VERSION 5.7 ;
  NOWIREEXTENSIONATPIN ON ;
  DIVIDERCHAR "/" ;
  BUSBITCHARS "[]" ;
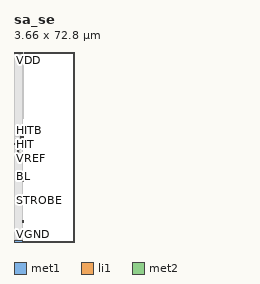
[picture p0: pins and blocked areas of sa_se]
MACRO sa_se
  CLASS BLOCK ;
  FOREIGN sa_se ;
  ORIGIN 0.300 -0.200 ;
  SIZE 3.660 BY 72.800 ;
  PIN VGND
    USE GROUND ;
    PORT
      LAYER met1 ;
        RECT -0.300 0.200 2.900 0.700 ;
    END
    PORT
      LAYER li1 ;
        RECT 2.900 7.550 3.320 8.450 ;
    END
    PORT
      LAYER li1 ;
        RECT 2.900 23.550 3.320 24.450 ;
    END
    PORT
      LAYER li1 ;
        RECT 2.900 39.550 3.320 40.450 ;
    END
  END VGND
  PIN VDD
      USE POWER ;
    ANTENNADIFFAREA 5.527200 ;
    PORT
      LAYER met2 ;
        RECT -0.300 72.300 2.900 72.800 ;
    END
  END VDD
  PIN BL
    ANTENNAGATEAREA 16.000000 ;
    PORT
      LAYER met2 ;
        RECT 1.150 25.100 1.430 25.700 ;
    END
  END BL
  PIN VREF
    ANTENNAGATEAREA 16.000000 ;
    PORT
      LAYER met2 ;
        RECT 1.150 34.600 1.430 35.200 ;
    END
  END VREF
  PIN HIT
    ANTENNAGATEAREA 12.000000 ;
    ANTENNADIFFAREA 3.723600 ;
    PORT
      LAYER met2 ;
        RECT 0.060 37.400 0.340 37.900 ;
    END
  END HIT
  PIN HITB
    ANTENNAGATEAREA 12.000000 ;
    ANTENNADIFFAREA 3.723600 ;
    PORT
      LAYER met2 ;
        RECT 2.260 40.000 2.540 40.500 ;
    END
  END HITB
  PIN STROBE
    ANTENNAGATEAREA 15.679999 ;
    PORT
      LAYER met2 ;
        RECT 2.800 16.000 3.080 16.500 ;
    END
  END STROBE
  OBS
      LAYER nwell ;
        RECT -0.300 47.500 3.150 73.000 ;
      LAYER li1 ;
        RECT 0.060 40.620 2.920 72.055 ;
        RECT 0.060 39.380 2.730 40.620 ;
        RECT 0.060 24.620 2.920 39.380 ;
        RECT 0.060 23.380 2.730 24.620 ;
        RECT 0.060 8.620 2.920 23.380 ;
        RECT 0.060 7.380 2.730 8.620 ;
        RECT 0.060 5.080 2.920 7.380 ;
      LAYER met1 ;
        RECT 0.010 0.980 3.130 72.160 ;
      LAYER met2 ;
        RECT 0.010 40.780 3.130 72.020 ;
        RECT 0.010 39.720 1.980 40.780 ;
        RECT 2.820 39.720 3.130 40.780 ;
        RECT 0.010 38.180 3.130 39.720 ;
        RECT 0.620 37.120 3.130 38.180 ;
        RECT 0.010 35.480 3.130 37.120 ;
        RECT 0.010 34.320 0.870 35.480 ;
        RECT 1.710 34.320 3.130 35.480 ;
        RECT 0.010 25.980 3.130 34.320 ;
        RECT 0.010 24.820 0.870 25.980 ;
        RECT 1.710 24.820 3.130 25.980 ;
        RECT 0.010 16.780 3.130 24.820 ;
        RECT 0.010 15.720 2.520 16.780 ;
        RECT 0.010 15.715 3.130 15.720 ;
  END
END sa_se
END LIBRARY

